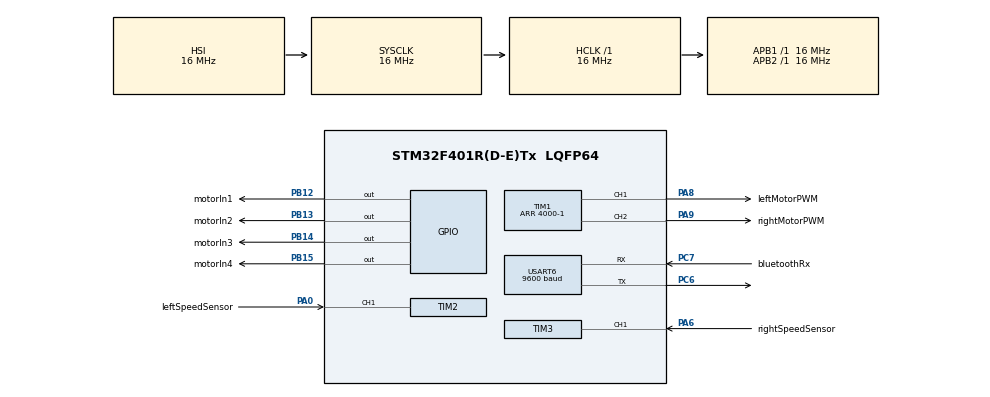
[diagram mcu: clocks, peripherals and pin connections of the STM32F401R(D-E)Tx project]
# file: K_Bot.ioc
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Mcu.Family=STM32F4
Mcu.Name=STM32F401R(D-E)Tx
Mcu.Package=LQFP64
NVIC.PriorityGroup=NVIC_PRIORITYGROUP_4
PA0-WKUP.GPIO_Label=leftSpeedSensor
PA0-WKUP.Signal=S_TIM2_CH1_ETR
PA13.Mode=Serial_Wire
PA13.Signal=SYS_JTMS-SWDIO
PA14.Mode=Serial_Wire
PA14.Signal=SYS_JTCK-SWCLK
PA6.GPIO_Label=rightSpeedSensor
PA6.Signal=S_TIM3_CH1
PA8.GPIO_Label=leftMotorPWM
PA8.Signal=S_TIM1_CH1
PA9.GPIO_Label=rightMotorPWM
PA9.Signal=S_TIM1_CH2
PB12.GPIO_Label=motorIn1
PB12.Signal=GPIO_Output
PB13.GPIO_Label=motorIn2
PB13.Signal=GPIO_Output
PB14.GPIO_Label=motorIn3
PB14.Signal=GPIO_Output
PB15.GPIO_Label=motorIn4
PB15.Signal=GPIO_Output
PC6.Mode=Asynchronous
PC6.Signal=USART6_TX
PC7.GPIO_Label=bluetoothRx
PC7.Mode=Asynchronous
PC7.Signal=USART6_RX
ProjectManager.HeapSize=0x200
ProjectManager.StackSize=0x400
ProjectManager.TargetToolchain=STM32CubeIDE
RCC.AHBFreq_Value=16000000
RCC.APB1Freq_Value=16000000
RCC.APB2Freq_Value=16000000
RCC.CortexFreq_Value=16000000
RCC.HSE_VALUE=25000000
RCC.HSI_VALUE=16000000
RCC.LSE_VALUE=32768
RCC.SYSCLKFreq_VALUE=16000000
RCC.VCOOutputFreq_Value=192000000
SH.S_TIM1_CH1.0=TIM1_CH1,PWM Generation1 CH1
SH.S_TIM1_CH2.0=TIM1_CH2,PWM Generation2 CH2
SH.S_TIM2_CH1_ETR.0=TIM2_CH1,PWM_Input_1
SH.S_TIM3_CH1.0=TIM3_CH1,PWM_Input_1
TIM1.AutoReloadPreload=TIM_AUTORELOAD_PRELOAD_ENABLE
TIM1.Channel-PWM\ Generation1\ CH1=TIM_CHANNEL_1
TIM1.Channel-PWM\ Generation2\ CH2=TIM_CHANNEL_2
TIM1.Period=4000-1
TIM2.AutoReloadPreload=TIM_AUTORELOAD_PRELOAD_ENABLE
TIM2.ICFilter_1=15
TIM2.ICFilter_2=15
TIM2.Period=1000-1
TIM2.Prescaler=1600-1
TIM3.AutoReloadPreload=TIM_AUTORELOAD_PRELOAD_ENABLE
TIM3.ICFilter_1=15
TIM3.ICFilter_2=15
TIM3.Period=1000-1
TIM3.Prescaler=1600-1
USART6.BaudRate=9600
USART6.Mode=MODE_RX
USART6.VirtualMode=VM_ASYNC
board=custom

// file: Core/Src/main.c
/* USER CODE BEGIN Header */
/**
  ******************************************************************************
  * @file           : main.c
  * @brief          : Main program body
  ******************************************************************************
  * @attention
  *
  * Copyright (c) 2022 STMicroelectronics.
  * All rights reserved.
  *
  * This software is licensed under terms that can be found in the LICENSE file
  * in the root directory of this software component.
  * If no LICENSE file comes with this software, it is provided AS-IS.
  *
  ******************************************************************************
  */
/* USER CODE END Header */
#include "main.h"

/* USER CODE BEGIN Includes */
#include <stdbool.h>
/* USER CODE END Includes */

/* USER CODE BEGIN PTD */
typedef enum
{
  LEFT_MOTOR = 0,
  RIGHT_MOTOR
}motor_t;

typedef struct
{
  TIM_HandleTypeDef* htim;
  motor_t type;
  uint32_t sensorPeriod;
  uint32_t speed;
}motorParam_t;
/* USER CODE END PTD */

/* USER CODE BEGIN PD */
#define MAX_MOTOR_SPEED	3999 //cycles
/* USER CODE END PD */

 TIM_HandleTypeDef htim1;
TIM_HandleTypeDef htim2;
TIM_HandleTypeDef htim3;

UART_HandleTypeDef huart6;

void SystemClock_Config(void);
static void MX_GPIO_Init(void);
static void MX_TIM2_Init(void);
static void MX_TIM3_Init(void);
static void MX_TIM1_Init(void);
static void MX_USART6_UART_Init(void);

/* USER CODE BEGIN 0 */
/**
 * @brief Get period of output wave from motor's speed sensor
 * in cycles. [Actual period(in milliseconds) = period(in cycles) / 10]
 * */
void GetMotorSensorPeriod(motorParam_t* motor)
{
  if((motor->htim->Instance->SR & TIM_SR_CC1IF) == TIM_SR_CC1IF)
  {
    motor->sensorPeriod = motor->htim->Instance->CCR1;
  }
}

/**
 * @brief Sets motor speed via PWM signal with 4kHz frequency.*/
void SetMotorSpeed(motorParam_t* motor)
{
  if(motor->speed > MAX_MOTOR_SPEED)
  {//Can't exceed the period (4000 cycles)
    motor->speed = MAX_MOTOR_SPEED;
  }
  switch(motor->type)
  {
    case LEFT_MOTOR:
      __HAL_TIM_SET_COMPARE(&htim1,TIM_CHANNEL_1,motor->speed);
      break;
    case RIGHT_MOTOR:
      __HAL_TIM_SET_COMPARE(&htim1,TIM_CHANNEL_2,motor->speed);
      break;
  }
}

/**
 * @brief Move motor forward*/
void AdvanceMotor(motorParam_t* motor)
{
  switch(motor->type)
  {
    case LEFT_MOTOR:
      HAL_GPIO_WritePin(motorIn1_GPIO_Port,motorIn1_Pin,GPIO_PIN_SET);
      HAL_GPIO_WritePin(motorIn2_GPIO_Port,motorIn2_Pin,GPIO_PIN_RESET);
      break;
    case RIGHT_MOTOR:
      HAL_GPIO_WritePin(motorIn3_GPIO_Port,motorIn3_Pin,GPIO_PIN_SET);
      HAL_GPIO_WritePin(motorIn4_GPIO_Port,motorIn4_Pin,GPIO_PIN_RESET);
      break;
  }
}

/**
 * @brief Move motor backward*/
void ReverseMotor(motorParam_t* motor)
{
  switch(motor->type)
  {
    case LEFT_MOTOR:
      HAL_GPIO_WritePin(motorIn1_GPIO_Port,motorIn1_Pin,GPIO_PIN_RESET);
      HAL_GPIO_WritePin(motorIn2_GPIO_Port,motorIn2_Pin,GPIO_PIN_SET);
      break;
    case RIGHT_MOTOR:
      HAL_GPIO_WritePin(motorIn3_GPIO_Port,motorIn3_Pin,GPIO_PIN_RESET);
      HAL_GPIO_WritePin(motorIn4_GPIO_Port,motorIn4_Pin,GPIO_PIN_SET);
      break;
  }
}

void StopMotors(void)
{//Stop left motor
  HAL_GPIO_WritePin(motorIn1_GPIO_Port,motorIn1_Pin,GPIO_PIN_RESET);
  HAL_GPIO_WritePin(motorIn2_GPIO_Port,motorIn2_Pin,GPIO_PIN_RESET);
  //Stop right motor
  HAL_GPIO_WritePin(motorIn3_GPIO_Port,motorIn3_Pin,GPIO_PIN_RESET);
  HAL_GPIO_WritePin(motorIn4_GPIO_Port,motorIn4_Pin,GPIO_PIN_RESET);
}

void InitMotorParam(motorParam_t* motor,
		    TIM_HandleTypeDef* htim,
		    motor_t type,
		    uint32_t sensorPeriod,
		    uint32_t speed)
{
  motor->htim = htim;
  motor->type = type;
  motor->sensorPeriod = sensorPeriod;
  motor->speed = speed;
}

/**
 * @brief Handles motor speed control*/
void RegulateMotorSpeed(motorParam_t* motor,uint32_t desiredPeriod)
{
  const uint8_t tolerance = 3; //cycles
  //The equation below is affected by battery voltage
  uint32_t desiredMotorSpeed = (5799 - 19*desiredPeriod); //review/experiment

  GetMotorSensorPeriod(motor);
  if(motor->sensorPeriod <= desiredPeriod)
  {
    if(motor->speed > (desiredMotorSpeed-tolerance))
    {
      motor->speed--;
    }
    else
    {
      motor->speed = desiredMotorSpeed;
    }
    SetMotorSpeed(motor);
  }
  else
  {
    if(motor->speed < (desiredMotorSpeed+tolerance))
    {
      motor->speed++;
    }
    else
    {
      motor->speed = desiredMotorSpeed;
    }
    SetMotorSpeed(motor);
  }
}

/**
 * @brief Returns data received from the K-Bot app via bluetooth*/
char GetBluetoothData(void)
{
  char btData = '\0';
  if((huart6.Instance->SR & USART_SR_RXNE) == USART_SR_RXNE)
  {
     btData = huart6.Instance->DR;
  }
  return btData;
}

/* USER CODE END 0 */

int main(void)
{

  /* MCU Configuration--------------------------------------------------------*/

  /* Reset of all peripherals, Initializes the Flash interface and the Systick. */
  HAL_Init();

  /* Configure the system clock */
  SystemClock_Config();

  /* Initialize all configured peripherals */
  MX_GPIO_Init();
  MX_TIM2_Init();
  MX_TIM3_Init();
  MX_TIM1_Init();
  MX_USART6_UART_Init();
  /* USER CODE BEGIN 2 */
  char appData = '\0';
  bool speedBalanceEnable = false;
  uint32_t targetPeriod = 115;
  motorParam_t leftMotor;
  motorParam_t rightMotor;

  InitMotorParam(&leftMotor,&htim2,LEFT_MOTOR,0,3999);
  InitMotorParam(&rightMotor,&htim3,RIGHT_MOTOR,0,3999);

  SetMotorSpeed(&leftMotor);
  ReverseMotor(&leftMotor);
  HAL_Delay(3000);
  /* USER CODE END 2 */

  /* Infinite loop */
  while (1)
  {
    RegulateMotorSpeed(&leftMotor,160); //test
    /* USER CODE BEGIN 3 */
    appData = GetBluetoothData();
    switch(appData)
    {
      case '0': //Pump control
	HAL_GPIO_TogglePin(pump_GPIO_Port,pump_Pin);
	speedBalanceEnable = false;
	break;
      case '1': //Brush control
	HAL_GPIO_TogglePin(brush_GPIO_Port,brush_Pin);
	speedBalanceEnable = false;
	break;
      case '2': //Move back
	ReverseMotor(&leftMotor);
	ReverseMotor(&rightMotor);
	speedBalanceEnable = true;
	break;
      case '3': //Turn left
	speedBalanceEnable = false;
	break;
      case '4': //Stop
	StopMotors();
	speedBalanceEnable = false;
	break;
      case '5': //Turn right
	speedBalanceEnable = false;
	break;
      case '6': //Move forward
	AdvanceMotor(&leftMotor);
	AdvanceMotor(&rightMotor);
	speedBalanceEnable = true;
	break;
    }
    //Speed adjustment
    if(speedBalanceEnable)
    {
	RegulateMotorSpeed(&leftMotor,targetPeriod);
	RegulateMotorSpeed(&rightMotor,targetPeriod);
    }

  }
  /* USER CODE END 3 */
}

void SystemClock_Config(void)
{
  RCC_OscInitTypeDef RCC_OscInitStruct = {0};
  RCC_ClkInitTypeDef RCC_ClkInitStruct = {0};

  /** Configure the main internal regulator output voltage
  */
  __HAL_RCC_PWR_CLK_ENABLE();
  __HAL_PWR_VOLTAGESCALING_CONFIG(PWR_REGULATOR_VOLTAGE_SCALE2);

  /** Initializes the RCC Oscillators according to the specified parameters
  * in the RCC_OscInitTypeDef structure.
  */
  RCC_OscInitStruct.OscillatorType = RCC_OSCILLATORTYPE_HSI;
  RCC_OscInitStruct.HSIState = RCC_HSI_ON;
  RCC_OscInitStruct.HSICalibrationValue = RCC_HSICALIBRATION_DEFAULT;
  RCC_OscInitStruct.PLL.PLLState = RCC_PLL_NONE;
  if (HAL_RCC_OscConfig(&RCC_OscInitStruct) != HAL_OK)
  {
    Error_Handler();
  }

  /** Initializes the CPU, AHB and APB buses clocks
  */
  RCC_ClkInitStruct.ClockType = RCC_CLOCKTYPE_HCLK|RCC_CLOCKTYPE_SYSCLK
                              |RCC_CLOCKTYPE_PCLK1|RCC_CLOCKTYPE_PCLK2;
  RCC_ClkInitStruct.SYSCLKSource = RCC_SYSCLKSOURCE_HSI;
  RCC_ClkInitStruct.AHBCLKDivider = RCC_SYSCLK_DIV1;
  RCC_ClkInitStruct.APB1CLKDivider = RCC_HCLK_DIV1;
  RCC_ClkInitStruct.APB2CLKDivider = RCC_HCLK_DIV1;

  if (HAL_RCC_ClockConfig(&RCC_ClkInitStruct, FLASH_LATENCY_0) != HAL_OK)
  {
    Error_Handler();
  }
}

static void MX_TIM1_Init(void)
{

  TIM_MasterConfigTypeDef sMasterConfig = {0};
  TIM_OC_InitTypeDef sConfigOC = {0};
  TIM_BreakDeadTimeConfigTypeDef sBreakDeadTimeConfig = {0};

  htim1.Instance = TIM1;
  htim1.Init.Prescaler = 0;
  htim1.Init.CounterMode = TIM_COUNTERMODE_UP;
  htim1.Init.Period = 4000-1;
  htim1.Init.ClockDivision = TIM_CLOCKDIVISION_DIV1;
  htim1.Init.RepetitionCounter = 0;
  htim1.Init.AutoReloadPreload = TIM_AUTORELOAD_PRELOAD_ENABLE;
  if (HAL_TIM_PWM_Init(&htim1) != HAL_OK)
  {
    Error_Handler();
  }
  sMasterConfig.MasterOutputTrigger = TIM_TRGO_RESET;
  sMasterConfig.MasterSlaveMode = TIM_MASTERSLAVEMODE_DISABLE;
  if (HAL_TIMEx_MasterConfigSynchronization(&htim1, &sMasterConfig) != HAL_OK)
  {
    Error_Handler();
  }
  sConfigOC.OCMode = TIM_OCMODE_PWM1;
  sConfigOC.Pulse = 0;
  sConfigOC.OCPolarity = TIM_OCPOLARITY_HIGH;
  sConfigOC.OCNPolarity = TIM_OCNPOLARITY_HIGH;
  sConfigOC.OCFastMode = TIM_OCFAST_DISABLE;
  sConfigOC.OCIdleState = TIM_OCIDLESTATE_RESET;
  sConfigOC.OCNIdleState = TIM_OCNIDLESTATE_RESET;
  if (HAL_TIM_PWM_ConfigChannel(&htim1, &sConfigOC, TIM_CHANNEL_1) != HAL_OK)
  {
    Error_Handler();
  }
  if (HAL_TIM_PWM_ConfigChannel(&htim1, &sConfigOC, TIM_CHANNEL_2) != HAL_OK)
  {
    Error_Handler();
  }
  sBreakDeadTimeConfig.OffStateRunMode = TIM_OSSR_DISABLE;
  sBreakDeadTimeConfig.OffStateIDLEMode = TIM_OSSI_DISABLE;
  sBreakDeadTimeConfig.LockLevel = TIM_LOCKLEVEL_OFF;
  sBreakDeadTimeConfig.DeadTime = 0;
  sBreakDeadTimeConfig.BreakState = TIM_BREAK_DISABLE;
  sBreakDeadTimeConfig.BreakPolarity = TIM_BREAKPOLARITY_HIGH;
  sBreakDeadTimeConfig.AutomaticOutput = TIM_AUTOMATICOUTPUT_DISABLE;
  if (HAL_TIMEx_ConfigBreakDeadTime(&htim1, &sBreakDeadTimeConfig) != HAL_OK)
  {
    Error_Handler();
  }
  /* USER CODE BEGIN TIM1_Init 2 */
  HAL_TIM_PWM_Start(&htim1,TIM_CHANNEL_1);
  HAL_TIM_PWM_Start(&htim1,TIM_CHANNEL_2);
  /* USER CODE END TIM1_Init 2 */
  HAL_TIM_MspPostInit(&htim1);

}

static void MX_TIM2_Init(void)
{

  TIM_SlaveConfigTypeDef sSlaveConfig = {0};
  TIM_IC_InitTypeDef sConfigIC = {0};
  TIM_MasterConfigTypeDef sMasterConfig = {0};

  htim2.Instance = TIM2;
  htim2.Init.Prescaler = 1600-1;
  htim2.Init.CounterMode = TIM_COUNTERMODE_UP;
  htim2.Init.Period = 1000-1;
  htim2.Init.ClockDivision = TIM_CLOCKDIVISION_DIV1;
  htim2.Init.AutoReloadPreload = TIM_AUTORELOAD_PRELOAD_ENABLE;
  if (HAL_TIM_IC_Init(&htim2) != HAL_OK)
  {
    Error_Handler();
  }
  sSlaveConfig.SlaveMode = TIM_SLAVEMODE_RESET;
  sSlaveConfig.InputTrigger = TIM_TS_TI1FP1;
  sSlaveConfig.TriggerPolarity = TIM_INPUTCHANNELPOLARITY_RISING;
  sSlaveConfig.TriggerPrescaler = TIM_ICPSC_DIV1;
  sSlaveConfig.TriggerFilter = 15;
  if (HAL_TIM_SlaveConfigSynchro(&htim2, &sSlaveConfig) != HAL_OK)
  {
    Error_Handler();
  }
  sConfigIC.ICPolarity = TIM_INPUTCHANNELPOLARITY_RISING;
  sConfigIC.ICSelection = TIM_ICSELECTION_DIRECTTI;
  sConfigIC.ICPrescaler = TIM_ICPSC_DIV1;
  sConfigIC.ICFilter = 15;
  if (HAL_TIM_IC_ConfigChannel(&htim2, &sConfigIC, TIM_CHANNEL_1) != HAL_OK)
  {
    Error_Handler();
  }
  sConfigIC.ICPolarity = TIM_INPUTCHANNELPOLARITY_FALLING;
  sConfigIC.ICSelection = TIM_ICSELECTION_INDIRECTTI;
  if (HAL_TIM_IC_ConfigChannel(&htim2, &sConfigIC, TIM_CHANNEL_2) != HAL_OK)
  {
    Error_Handler();
  }
  sMasterConfig.MasterOutputTrigger = TIM_TRGO_RESET;
  sMasterConfig.MasterSlaveMode = TIM_MASTERSLAVEMODE_DISABLE;
  if (HAL_TIMEx_MasterConfigSynchronization(&htim2, &sMasterConfig) != HAL_OK)
  {
    Error_Handler();
  }
  /* USER CODE BEGIN TIM2_Init 2 */
  HAL_TIM_IC_Start(&htim2,TIM_CHANNEL_1);
  /* USER CODE END TIM2_Init 2 */

}

static void MX_TIM3_Init(void)
{

  TIM_SlaveConfigTypeDef sSlaveConfig = {0};
  TIM_IC_InitTypeDef sConfigIC = {0};
  TIM_MasterConfigTypeDef sMasterConfig = {0};

  htim3.Instance = TIM3;
  htim3.Init.Prescaler = 1600-1;
  htim3.Init.CounterMode = TIM_COUNTERMODE_UP;
  htim3.Init.Period = 1000-1;
  htim3.Init.ClockDivision = TIM_CLOCKDIVISION_DIV1;
  htim3.Init.AutoReloadPreload = TIM_AUTORELOAD_PRELOAD_ENABLE;
  if (HAL_TIM_IC_Init(&htim3) != HAL_OK)
  {
    Error_Handler();
  }
  sSlaveConfig.SlaveMode = TIM_SLAVEMODE_RESET;
  sSlaveConfig.InputTrigger = TIM_TS_TI1FP1;
  sSlaveConfig.TriggerPolarity = TIM_INPUTCHANNELPOLARITY_RISING;
  sSlaveConfig.TriggerPrescaler = TIM_ICPSC_DIV1;
  sSlaveConfig.TriggerFilter = 15;
  if (HAL_TIM_SlaveConfigSynchro(&htim3, &sSlaveConfig) != HAL_OK)
  {
    Error_Handler();
  }
  sConfigIC.ICPolarity = TIM_INPUTCHANNELPOLARITY_RISING;
  sConfigIC.ICSelection = TIM_ICSELECTION_DIRECTTI;
  sConfigIC.ICPrescaler = TIM_ICPSC_DIV1;
  sConfigIC.ICFilter = 15;
  if (HAL_TIM_IC_ConfigChannel(&htim3, &sConfigIC, TIM_CHANNEL_1) != HAL_OK)
  {
    Error_Handler();
  }
  sConfigIC.ICPolarity = TIM_INPUTCHANNELPOLARITY_FALLING;
  sConfigIC.ICSelection = TIM_ICSELECTION_INDIRECTTI;
  if (HAL_TIM_IC_ConfigChannel(&htim3, &sConfigIC, TIM_CHANNEL_2) != HAL_OK)
  {
    Error_Handler();
  }
  sMasterConfig.MasterOutputTrigger = TIM_TRGO_RESET;
  sMasterConfig.MasterSlaveMode = TIM_MASTERSLAVEMODE_DISABLE;
  if (HAL_TIMEx_MasterConfigSynchronization(&htim3, &sMasterConfig) != HAL_OK)
  {
    Error_Handler();
  }
  /* USER CODE BEGIN TIM3_Init 2 */
  HAL_TIM_IC_Start(&htim3,TIM_CHANNEL_1);
  /* USER CODE END TIM3_Init 2 */

}

static void MX_USART6_UART_Init(void)
{

  huart6.Instance = USART6;
  huart6.Init.BaudRate = 9600;
  huart6.Init.WordLength = UART_WORDLENGTH_8B;
  huart6.Init.StopBits = UART_STOPBITS_1;
  huart6.Init.Parity = UART_PARITY_NONE;
  huart6.Init.Mode = UART_MODE_RX;
  huart6.Init.HwFlowCtl = UART_HWCONTROL_NONE;
  huart6.Init.OverSampling = UART_OVERSAMPLING_16;
  if (HAL_UART_Init(&huart6) != HAL_OK)
  {
    Error_Handler();
  }

}

static void MX_GPIO_Init(void)
{
  GPIO_InitTypeDef GPIO_InitStruct = {0};

  /* GPIO Ports Clock Enable */
  __HAL_RCC_GPIOA_CLK_ENABLE();
  __HAL_RCC_GPIOB_CLK_ENABLE();
  __HAL_RCC_GPIOC_CLK_ENABLE();

  /*Configure GPIO pin Output Level */
  HAL_GPIO_WritePin(GPIOB, motorIn1_Pin|motorIn2_Pin|motorIn3_Pin|motorIn4_Pin, GPIO_PIN_RESET);

  /*Configure GPIO pin Output Level */
  HAL_GPIO_WritePin(GPIOC, pump_Pin|brush_Pin, GPIO_PIN_RESET);

  /*Configure GPIO pins : motorIn1_Pin motorIn2_Pin motorIn3_Pin motorIn4_Pin */
  GPIO_InitStruct.Pin = motorIn1_Pin|motorIn2_Pin|motorIn3_Pin|motorIn4_Pin;
  GPIO_InitStruct.Mode = GPIO_MODE_OUTPUT_PP;
  GPIO_InitStruct.Pull = GPIO_NOPULL;
  GPIO_InitStruct.Speed = GPIO_SPEED_FREQ_LOW;
  HAL_GPIO_Init(GPIOB, &GPIO_InitStruct);

  /*Configure GPIO pins : pump_Pin brush_Pin */
  GPIO_InitStruct.Pin = pump_Pin|brush_Pin;
  GPIO_InitStruct.Mode = GPIO_MODE_OUTPUT_PP;
  GPIO_InitStruct.Pull = GPIO_NOPULL;
  GPIO_InitStruct.Speed = GPIO_SPEED_FREQ_LOW;
  HAL_GPIO_Init(GPIOC, &GPIO_InitStruct);

}

void Error_Handler(void)
{
  __disable_irq();
  while (1)
  {
  }
}
